VERSION 5.7 ;
BUSBITCHARS "[]" ;
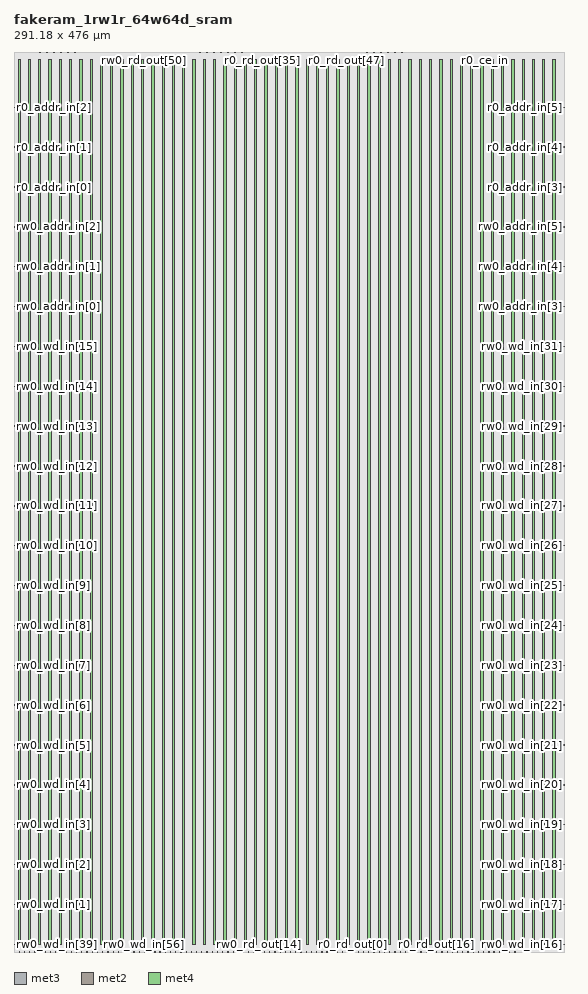
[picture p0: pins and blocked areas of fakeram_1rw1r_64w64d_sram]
MACRO fakeram_1rw1r_64w64d_sram
  FOREIGN fakeram_1rw1r_64w64d_sram 0 0 ;
  SYMMETRY X Y R90 ;
  SIZE 291.180 BY 476.000 ;
  CLASS BLOCK ;
  PIN rw0_wd_in[0]
    DIRECTION INPUT ;
    USE SIGNAL ;
    SHAPE ABUTMENT ;
    PORT
      LAYER met3 ;
      RECT 0.000 3.930 0.900 4.230 ;
    END
  END rw0_wd_in[0]
  PIN rw0_wd_in[1]
    DIRECTION INPUT ;
    USE SIGNAL ;
    SHAPE ABUTMENT ;
    PORT
      LAYER met3 ;
      RECT 0.000 25.010 0.900 25.310 ;
    END
  END rw0_wd_in[1]
  PIN rw0_wd_in[2]
    DIRECTION INPUT ;
    USE SIGNAL ;
    SHAPE ABUTMENT ;
    PORT
      LAYER met3 ;
      RECT 0.000 46.090 0.900 46.390 ;
    END
  END rw0_wd_in[2]
  PIN rw0_wd_in[3]
    DIRECTION INPUT ;
    USE SIGNAL ;
    SHAPE ABUTMENT ;
    PORT
      LAYER met3 ;
      RECT 0.000 67.170 0.900 67.470 ;
    END
  END rw0_wd_in[3]
  PIN rw0_wd_in[4]
    DIRECTION INPUT ;
    USE SIGNAL ;
    SHAPE ABUTMENT ;
    PORT
      LAYER met3 ;
      RECT 0.000 88.250 0.900 88.550 ;
    END
  END rw0_wd_in[4]
  PIN rw0_wd_in[5]
    DIRECTION INPUT ;
    USE SIGNAL ;
    SHAPE ABUTMENT ;
    PORT
      LAYER met3 ;
      RECT 0.000 109.330 0.900 109.630 ;
    END
  END rw0_wd_in[5]
  PIN rw0_wd_in[6]
    DIRECTION INPUT ;
    USE SIGNAL ;
    SHAPE ABUTMENT ;
    PORT
      LAYER met3 ;
      RECT 0.000 130.410 0.900 130.710 ;
    END
  END rw0_wd_in[6]
  PIN rw0_wd_in[7]
    DIRECTION INPUT ;
    USE SIGNAL ;
    SHAPE ABUTMENT ;
    PORT
      LAYER met3 ;
      RECT 0.000 151.490 0.900 151.790 ;
    END
  END rw0_wd_in[7]
  PIN rw0_wd_in[8]
    DIRECTION INPUT ;
    USE SIGNAL ;
    SHAPE ABUTMENT ;
    PORT
      LAYER met3 ;
      RECT 0.000 172.570 0.900 172.870 ;
    END
  END rw0_wd_in[8]
  PIN rw0_wd_in[9]
    DIRECTION INPUT ;
    USE SIGNAL ;
    SHAPE ABUTMENT ;
    PORT
      LAYER met3 ;
      RECT 0.000 193.650 0.900 193.950 ;
    END
  END rw0_wd_in[9]
  PIN rw0_wd_in[10]
    DIRECTION INPUT ;
    USE SIGNAL ;
    SHAPE ABUTMENT ;
    PORT
      LAYER met3 ;
      RECT 0.000 214.730 0.900 215.030 ;
    END
  END rw0_wd_in[10]
  PIN rw0_wd_in[11]
    DIRECTION INPUT ;
    USE SIGNAL ;
    SHAPE ABUTMENT ;
    PORT
      LAYER met3 ;
      RECT 0.000 235.810 0.900 236.110 ;
    END
  END rw0_wd_in[11]
  PIN rw0_wd_in[12]
    DIRECTION INPUT ;
    USE SIGNAL ;
    SHAPE ABUTMENT ;
    PORT
      LAYER met3 ;
      RECT 0.000 256.890 0.900 257.190 ;
    END
  END rw0_wd_in[12]
  PIN rw0_wd_in[13]
    DIRECTION INPUT ;
    USE SIGNAL ;
    SHAPE ABUTMENT ;
    PORT
      LAYER met3 ;
      RECT 0.000 277.970 0.900 278.270 ;
    END
  END rw0_wd_in[13]
  PIN rw0_wd_in[14]
    DIRECTION INPUT ;
    USE SIGNAL ;
    SHAPE ABUTMENT ;
    PORT
      LAYER met3 ;
      RECT 0.000 299.050 0.900 299.350 ;
    END
  END rw0_wd_in[14]
  PIN rw0_wd_in[15]
    DIRECTION INPUT ;
    USE SIGNAL ;
    SHAPE ABUTMENT ;
    PORT
      LAYER met3 ;
      RECT 0.000 320.130 0.900 320.430 ;
    END
  END rw0_wd_in[15]
  PIN rw0_wd_in[16]
    DIRECTION INPUT ;
    USE SIGNAL ;
    SHAPE ABUTMENT ;
    PORT
      LAYER met3 ;
      RECT 290.280 3.930 291.180 4.230 ;
    END
  END rw0_wd_in[16]
  PIN rw0_wd_in[17]
    DIRECTION INPUT ;
    USE SIGNAL ;
    SHAPE ABUTMENT ;
    PORT
      LAYER met3 ;
      RECT 290.280 25.010 291.180 25.310 ;
    END
  END rw0_wd_in[17]
  PIN rw0_wd_in[18]
    DIRECTION INPUT ;
    USE SIGNAL ;
    SHAPE ABUTMENT ;
    PORT
      LAYER met3 ;
      RECT 290.280 46.090 291.180 46.390 ;
    END
  END rw0_wd_in[18]
  PIN rw0_wd_in[19]
    DIRECTION INPUT ;
    USE SIGNAL ;
    SHAPE ABUTMENT ;
    PORT
      LAYER met3 ;
      RECT 290.280 67.170 291.180 67.470 ;
    END
  END rw0_wd_in[19]
  PIN rw0_wd_in[20]
    DIRECTION INPUT ;
    USE SIGNAL ;
    SHAPE ABUTMENT ;
    PORT
      LAYER met3 ;
      RECT 290.280 88.250 291.180 88.550 ;
    END
  END rw0_wd_in[20]
  PIN rw0_wd_in[21]
    DIRECTION INPUT ;
    USE SIGNAL ;
    SHAPE ABUTMENT ;
    PORT
      LAYER met3 ;
      RECT 290.280 109.330 291.180 109.630 ;
    END
  END rw0_wd_in[21]
  PIN rw0_wd_in[22]
    DIRECTION INPUT ;
    USE SIGNAL ;
    SHAPE ABUTMENT ;
    PORT
      LAYER met3 ;
      RECT 290.280 130.410 291.180 130.710 ;
    END
  END rw0_wd_in[22]
  PIN rw0_wd_in[23]
    DIRECTION INPUT ;
    USE SIGNAL ;
    SHAPE ABUTMENT ;
    PORT
      LAYER met3 ;
      RECT 290.280 151.490 291.180 151.790 ;
    END
  END rw0_wd_in[23]
  PIN rw0_wd_in[24]
    DIRECTION INPUT ;
    USE SIGNAL ;
    SHAPE ABUTMENT ;
    PORT
      LAYER met3 ;
      RECT 290.280 172.570 291.180 172.870 ;
    END
  END rw0_wd_in[24]
  PIN rw0_wd_in[25]
    DIRECTION INPUT ;
    USE SIGNAL ;
    SHAPE ABUTMENT ;
    PORT
      LAYER met3 ;
      RECT 290.280 193.650 291.180 193.950 ;
    END
  END rw0_wd_in[25]
  PIN rw0_wd_in[26]
    DIRECTION INPUT ;
    USE SIGNAL ;
    SHAPE ABUTMENT ;
    PORT
      LAYER met3 ;
      RECT 290.280 214.730 291.180 215.030 ;
    END
  END rw0_wd_in[26]
  PIN rw0_wd_in[27]
    DIRECTION INPUT ;
    USE SIGNAL ;
    SHAPE ABUTMENT ;
    PORT
      LAYER met3 ;
      RECT 290.280 235.810 291.180 236.110 ;
    END
  END rw0_wd_in[27]
  PIN rw0_wd_in[28]
    DIRECTION INPUT ;
    USE SIGNAL ;
    SHAPE ABUTMENT ;
    PORT
      LAYER met3 ;
      RECT 290.280 256.890 291.180 257.190 ;
    END
  END rw0_wd_in[28]
  PIN rw0_wd_in[29]
    DIRECTION INPUT ;
    USE SIGNAL ;
    SHAPE ABUTMENT ;
    PORT
      LAYER met3 ;
      RECT 290.280 277.970 291.180 278.270 ;
    END
  END rw0_wd_in[29]
  PIN rw0_wd_in[30]
    DIRECTION INPUT ;
    USE SIGNAL ;
    SHAPE ABUTMENT ;
    PORT
      LAYER met3 ;
      RECT 290.280 299.050 291.180 299.350 ;
    END
  END rw0_wd_in[30]
  PIN rw0_wd_in[31]
    DIRECTION INPUT ;
    USE SIGNAL ;
    SHAPE ABUTMENT ;
    PORT
      LAYER met3 ;
      RECT 290.280 320.130 291.180 320.430 ;
    END
  END rw0_wd_in[31]
  PIN rw0_wd_in[32]
    DIRECTION INPUT ;
    USE SIGNAL ;
    SHAPE ABUTMENT ;
    PORT
      LAYER met2 ;
      RECT 2.690 0.000 2.830 0.420 ;
    END
  END rw0_wd_in[32]
  PIN rw0_wd_in[33]
    DIRECTION INPUT ;
    USE SIGNAL ;
    SHAPE ABUTMENT ;
    PORT
      LAYER met2 ;
      RECT 5.450 0.000 5.590 0.420 ;
    END
  END rw0_wd_in[33]
  PIN rw0_wd_in[34]
    DIRECTION INPUT ;
    USE SIGNAL ;
    SHAPE ABUTMENT ;
    PORT
      LAYER met2 ;
      RECT 8.210 0.000 8.350 0.420 ;
    END
  END rw0_wd_in[34]
  PIN rw0_wd_in[35]
    DIRECTION INPUT ;
    USE SIGNAL ;
    SHAPE ABUTMENT ;
    PORT
      LAYER met2 ;
      RECT 10.970 0.000 11.110 0.420 ;
    END
  END rw0_wd_in[35]
  PIN rw0_wd_in[36]
    DIRECTION INPUT ;
    USE SIGNAL ;
    SHAPE ABUTMENT ;
    PORT
      LAYER met2 ;
      RECT 13.730 0.000 13.870 0.420 ;
    END
  END rw0_wd_in[36]
  PIN rw0_wd_in[37]
    DIRECTION INPUT ;
    USE SIGNAL ;
    SHAPE ABUTMENT ;
    PORT
      LAYER met2 ;
      RECT 16.490 0.000 16.630 0.420 ;
    END
  END rw0_wd_in[37]
  PIN rw0_wd_in[38]
    DIRECTION INPUT ;
    USE SIGNAL ;
    SHAPE ABUTMENT ;
    PORT
      LAYER met2 ;
      RECT 19.250 0.000 19.390 0.420 ;
    END
  END rw0_wd_in[38]
  PIN rw0_wd_in[39]
    DIRECTION INPUT ;
    USE SIGNAL ;
    SHAPE ABUTMENT ;
    PORT
      LAYER met2 ;
      RECT 22.010 0.000 22.150 0.420 ;
    END
  END rw0_wd_in[39]
  PIN rw0_wd_in[40]
    DIRECTION INPUT ;
    USE SIGNAL ;
    SHAPE ABUTMENT ;
    PORT
      LAYER met2 ;
      RECT 24.770 0.000 24.910 0.420 ;
    END
  END rw0_wd_in[40]
  PIN rw0_wd_in[41]
    DIRECTION INPUT ;
    USE SIGNAL ;
    SHAPE ABUTMENT ;
    PORT
      LAYER met2 ;
      RECT 27.530 0.000 27.670 0.420 ;
    END
  END rw0_wd_in[41]
  PIN rw0_wd_in[42]
    DIRECTION INPUT ;
    USE SIGNAL ;
    SHAPE ABUTMENT ;
    PORT
      LAYER met2 ;
      RECT 30.290 0.000 30.430 0.420 ;
    END
  END rw0_wd_in[42]
  PIN rw0_wd_in[43]
    DIRECTION INPUT ;
    USE SIGNAL ;
    SHAPE ABUTMENT ;
    PORT
      LAYER met2 ;
      RECT 33.050 0.000 33.190 0.420 ;
    END
  END rw0_wd_in[43]
  PIN rw0_wd_in[44]
    DIRECTION INPUT ;
    USE SIGNAL ;
    SHAPE ABUTMENT ;
    PORT
      LAYER met2 ;
      RECT 35.810 0.000 35.950 0.420 ;
    END
  END rw0_wd_in[44]
  PIN rw0_wd_in[45]
    DIRECTION INPUT ;
    USE SIGNAL ;
    SHAPE ABUTMENT ;
    PORT
      LAYER met2 ;
      RECT 38.570 0.000 38.710 0.420 ;
    END
  END rw0_wd_in[45]
  PIN rw0_wd_in[46]
    DIRECTION INPUT ;
    USE SIGNAL ;
    SHAPE ABUTMENT ;
    PORT
      LAYER met2 ;
      RECT 41.330 0.000 41.470 0.420 ;
    END
  END rw0_wd_in[46]
  PIN rw0_wd_in[47]
    DIRECTION INPUT ;
    USE SIGNAL ;
    SHAPE ABUTMENT ;
    PORT
      LAYER met2 ;
      RECT 44.090 0.000 44.230 0.420 ;
    END
  END rw0_wd_in[47]
  PIN rw0_wd_in[48]
    DIRECTION INPUT ;
    USE SIGNAL ;
    SHAPE ABUTMENT ;
    PORT
      LAYER met2 ;
      RECT 46.850 0.000 46.990 0.420 ;
    END
  END rw0_wd_in[48]
  PIN rw0_wd_in[49]
    DIRECTION INPUT ;
    USE SIGNAL ;
    SHAPE ABUTMENT ;
    PORT
      LAYER met2 ;
      RECT 49.610 0.000 49.750 0.420 ;
    END
  END rw0_wd_in[49]
  PIN rw0_wd_in[50]
    DIRECTION INPUT ;
    USE SIGNAL ;
    SHAPE ABUTMENT ;
    PORT
      LAYER met2 ;
      RECT 52.370 0.000 52.510 0.420 ;
    END
  END rw0_wd_in[50]
  PIN rw0_wd_in[51]
    DIRECTION INPUT ;
    USE SIGNAL ;
    SHAPE ABUTMENT ;
    PORT
      LAYER met2 ;
      RECT 55.130 0.000 55.270 0.420 ;
    END
  END rw0_wd_in[51]
  PIN rw0_wd_in[52]
    DIRECTION INPUT ;
    USE SIGNAL ;
    SHAPE ABUTMENT ;
    PORT
      LAYER met2 ;
      RECT 57.890 0.000 58.030 0.420 ;
    END
  END rw0_wd_in[52]
  PIN rw0_wd_in[53]
    DIRECTION INPUT ;
    USE SIGNAL ;
    SHAPE ABUTMENT ;
    PORT
      LAYER met2 ;
      RECT 60.650 0.000 60.790 0.420 ;
    END
  END rw0_wd_in[53]
  PIN rw0_wd_in[54]
    DIRECTION INPUT ;
    USE SIGNAL ;
    SHAPE ABUTMENT ;
    PORT
      LAYER met2 ;
      RECT 63.410 0.000 63.550 0.420 ;
    END
  END rw0_wd_in[54]
  PIN rw0_wd_in[55]
    DIRECTION INPUT ;
    USE SIGNAL ;
    SHAPE ABUTMENT ;
    PORT
      LAYER met2 ;
      RECT 66.170 0.000 66.310 0.420 ;
    END
  END rw0_wd_in[55]
  PIN rw0_wd_in[56]
    DIRECTION INPUT ;
    USE SIGNAL ;
    SHAPE ABUTMENT ;
    PORT
      LAYER met2 ;
      RECT 68.930 0.000 69.070 0.420 ;
    END
  END rw0_wd_in[56]
  PIN rw0_wd_in[57]
    DIRECTION INPUT ;
    USE SIGNAL ;
    SHAPE ABUTMENT ;
    PORT
      LAYER met2 ;
      RECT 71.690 0.000 71.830 0.420 ;
    END
  END rw0_wd_in[57]
  PIN rw0_wd_in[58]
    DIRECTION INPUT ;
    USE SIGNAL ;
    SHAPE ABUTMENT ;
    PORT
      LAYER met2 ;
      RECT 74.450 0.000 74.590 0.420 ;
    END
  END rw0_wd_in[58]
  PIN rw0_wd_in[59]
    DIRECTION INPUT ;
    USE SIGNAL ;
    SHAPE ABUTMENT ;
    PORT
      LAYER met2 ;
      RECT 77.210 0.000 77.350 0.420 ;
    END
  END rw0_wd_in[59]
  PIN rw0_wd_in[60]
    DIRECTION INPUT ;
    USE SIGNAL ;
    SHAPE ABUTMENT ;
    PORT
      LAYER met2 ;
      RECT 79.970 0.000 80.110 0.420 ;
    END
  END rw0_wd_in[60]
  PIN rw0_wd_in[61]
    DIRECTION INPUT ;
    USE SIGNAL ;
    SHAPE ABUTMENT ;
    PORT
      LAYER met2 ;
      RECT 82.730 0.000 82.870 0.420 ;
    END
  END rw0_wd_in[61]
  PIN rw0_wd_in[62]
    DIRECTION INPUT ;
    USE SIGNAL ;
    SHAPE ABUTMENT ;
    PORT
      LAYER met2 ;
      RECT 85.490 0.000 85.630 0.420 ;
    END
  END rw0_wd_in[62]
  PIN rw0_wd_in[63]
    DIRECTION INPUT ;
    USE SIGNAL ;
    SHAPE ABUTMENT ;
    PORT
      LAYER met2 ;
      RECT 88.250 0.000 88.390 0.420 ;
    END
  END rw0_wd_in[63]
  PIN rw0_rd_out[0]
    DIRECTION OUTPUT ;
    USE SIGNAL ;
    SHAPE ABUTMENT ;
    PORT
      LAYER met2 ;
      RECT 91.010 0.000 91.150 0.420 ;
    END
  END rw0_rd_out[0]
  PIN rw0_rd_out[1]
    DIRECTION OUTPUT ;
    USE SIGNAL ;
    SHAPE ABUTMENT ;
    PORT
      LAYER met2 ;
      RECT 93.770 0.000 93.910 0.420 ;
    END
  END rw0_rd_out[1]
  PIN rw0_rd_out[2]
    DIRECTION OUTPUT ;
    USE SIGNAL ;
    SHAPE ABUTMENT ;
    PORT
      LAYER met2 ;
      RECT 96.530 0.000 96.670 0.420 ;
    END
  END rw0_rd_out[2]
  PIN rw0_rd_out[3]
    DIRECTION OUTPUT ;
    USE SIGNAL ;
    SHAPE ABUTMENT ;
    PORT
      LAYER met2 ;
      RECT 99.290 0.000 99.430 0.420 ;
    END
  END rw0_rd_out[3]
  PIN rw0_rd_out[4]
    DIRECTION OUTPUT ;
    USE SIGNAL ;
    SHAPE ABUTMENT ;
    PORT
      LAYER met2 ;
      RECT 102.050 0.000 102.190 0.420 ;
    END
  END rw0_rd_out[4]
  PIN rw0_rd_out[5]
    DIRECTION OUTPUT ;
    USE SIGNAL ;
    SHAPE ABUTMENT ;
    PORT
      LAYER met2 ;
      RECT 104.810 0.000 104.950 0.420 ;
    END
  END rw0_rd_out[5]
  PIN rw0_rd_out[6]
    DIRECTION OUTPUT ;
    USE SIGNAL ;
    SHAPE ABUTMENT ;
    PORT
      LAYER met2 ;
      RECT 107.570 0.000 107.710 0.420 ;
    END
  END rw0_rd_out[6]
  PIN rw0_rd_out[7]
    DIRECTION OUTPUT ;
    USE SIGNAL ;
    SHAPE ABUTMENT ;
    PORT
      LAYER met2 ;
      RECT 110.330 0.000 110.470 0.420 ;
    END
  END rw0_rd_out[7]
  PIN rw0_rd_out[8]
    DIRECTION OUTPUT ;
    USE SIGNAL ;
    SHAPE ABUTMENT ;
    PORT
      LAYER met2 ;
      RECT 113.090 0.000 113.230 0.420 ;
    END
  END rw0_rd_out[8]
  PIN rw0_rd_out[9]
    DIRECTION OUTPUT ;
    USE SIGNAL ;
    SHAPE ABUTMENT ;
    PORT
      LAYER met2 ;
      RECT 115.850 0.000 115.990 0.420 ;
    END
  END rw0_rd_out[9]
  PIN rw0_rd_out[10]
    DIRECTION OUTPUT ;
    USE SIGNAL ;
    SHAPE ABUTMENT ;
    PORT
      LAYER met2 ;
      RECT 118.610 0.000 118.750 0.420 ;
    END
  END rw0_rd_out[10]
  PIN rw0_rd_out[11]
    DIRECTION OUTPUT ;
    USE SIGNAL ;
    SHAPE ABUTMENT ;
    PORT
      LAYER met2 ;
      RECT 121.370 0.000 121.510 0.420 ;
    END
  END rw0_rd_out[11]
  PIN rw0_rd_out[12]
    DIRECTION OUTPUT ;
    USE SIGNAL ;
    SHAPE ABUTMENT ;
    PORT
      LAYER met2 ;
      RECT 124.130 0.000 124.270 0.420 ;
    END
  END rw0_rd_out[12]
  PIN rw0_rd_out[13]
    DIRECTION OUTPUT ;
    USE SIGNAL ;
    SHAPE ABUTMENT ;
    PORT
      LAYER met2 ;
      RECT 126.890 0.000 127.030 0.420 ;
    END
  END rw0_rd_out[13]
  PIN rw0_rd_out[14]
    DIRECTION OUTPUT ;
    USE SIGNAL ;
    SHAPE ABUTMENT ;
    PORT
      LAYER met2 ;
      RECT 129.650 0.000 129.790 0.420 ;
    END
  END rw0_rd_out[14]
  PIN rw0_rd_out[15]
    DIRECTION OUTPUT ;
    USE SIGNAL ;
    SHAPE ABUTMENT ;
    PORT
      LAYER met2 ;
      RECT 132.410 0.000 132.550 0.420 ;
    END
  END rw0_rd_out[15]
  PIN rw0_rd_out[16]
    DIRECTION OUTPUT ;
    USE SIGNAL ;
    SHAPE ABUTMENT ;
    PORT
      LAYER met2 ;
      RECT 135.170 0.000 135.310 0.420 ;
    END
  END rw0_rd_out[16]
  PIN rw0_rd_out[17]
    DIRECTION OUTPUT ;
    USE SIGNAL ;
    SHAPE ABUTMENT ;
    PORT
      LAYER met2 ;
      RECT 137.930 0.000 138.070 0.420 ;
    END
  END rw0_rd_out[17]
  PIN rw0_rd_out[18]
    DIRECTION OUTPUT ;
    USE SIGNAL ;
    SHAPE ABUTMENT ;
    PORT
      LAYER met2 ;
      RECT 140.690 0.000 140.830 0.420 ;
    END
  END rw0_rd_out[18]
  PIN rw0_rd_out[19]
    DIRECTION OUTPUT ;
    USE SIGNAL ;
    SHAPE ABUTMENT ;
    PORT
      LAYER met2 ;
      RECT 143.450 0.000 143.590 0.420 ;
    END
  END rw0_rd_out[19]
  PIN rw0_rd_out[20]
    DIRECTION OUTPUT ;
    USE SIGNAL ;
    SHAPE ABUTMENT ;
    PORT
      LAYER met2 ;
      RECT 146.210 0.000 146.350 0.420 ;
    END
  END rw0_rd_out[20]
  PIN rw0_rd_out[21]
    DIRECTION OUTPUT ;
    USE SIGNAL ;
    SHAPE ABUTMENT ;
    PORT
      LAYER met2 ;
      RECT 148.970 0.000 149.110 0.420 ;
    END
  END rw0_rd_out[21]
  PIN rw0_rd_out[22]
    DIRECTION OUTPUT ;
    USE SIGNAL ;
    SHAPE ABUTMENT ;
    PORT
      LAYER met2 ;
      RECT 151.730 0.000 151.870 0.420 ;
    END
  END rw0_rd_out[22]
  PIN rw0_rd_out[23]
    DIRECTION OUTPUT ;
    USE SIGNAL ;
    SHAPE ABUTMENT ;
    PORT
      LAYER met2 ;
      RECT 154.490 0.000 154.630 0.420 ;
    END
  END rw0_rd_out[23]
  PIN rw0_rd_out[24]
    DIRECTION OUTPUT ;
    USE SIGNAL ;
    SHAPE ABUTMENT ;
    PORT
      LAYER met2 ;
      RECT 157.250 0.000 157.390 0.420 ;
    END
  END rw0_rd_out[24]
  PIN rw0_rd_out[25]
    DIRECTION OUTPUT ;
    USE SIGNAL ;
    SHAPE ABUTMENT ;
    PORT
      LAYER met2 ;
      RECT 160.010 0.000 160.150 0.420 ;
    END
  END rw0_rd_out[25]
  PIN rw0_rd_out[26]
    DIRECTION OUTPUT ;
    USE SIGNAL ;
    SHAPE ABUTMENT ;
    PORT
      LAYER met2 ;
      RECT 162.770 0.000 162.910 0.420 ;
    END
  END rw0_rd_out[26]
  PIN rw0_rd_out[27]
    DIRECTION OUTPUT ;
    USE SIGNAL ;
    SHAPE ABUTMENT ;
    PORT
      LAYER met2 ;
      RECT 165.530 0.000 165.670 0.420 ;
    END
  END rw0_rd_out[27]
  PIN rw0_rd_out[28]
    DIRECTION OUTPUT ;
    USE SIGNAL ;
    SHAPE ABUTMENT ;
    PORT
      LAYER met2 ;
      RECT 168.290 0.000 168.430 0.420 ;
    END
  END rw0_rd_out[28]
  PIN rw0_rd_out[29]
    DIRECTION OUTPUT ;
    USE SIGNAL ;
    SHAPE ABUTMENT ;
    PORT
      LAYER met2 ;
      RECT 171.050 0.000 171.190 0.420 ;
    END
  END rw0_rd_out[29]
  PIN rw0_rd_out[30]
    DIRECTION OUTPUT ;
    USE SIGNAL ;
    SHAPE ABUTMENT ;
    PORT
      LAYER met2 ;
      RECT 173.810 0.000 173.950 0.420 ;
    END
  END rw0_rd_out[30]
  PIN rw0_rd_out[31]
    DIRECTION OUTPUT ;
    USE SIGNAL ;
    SHAPE ABUTMENT ;
    PORT
      LAYER met2 ;
      RECT 176.570 0.000 176.710 0.420 ;
    END
  END rw0_rd_out[31]
  PIN rw0_rd_out[32]
    DIRECTION OUTPUT ;
    USE SIGNAL ;
    SHAPE ABUTMENT ;
    PORT
      LAYER met2 ;
      RECT 2.690 475.580 2.830 476.000 ;
    END
  END rw0_rd_out[32]
  PIN rw0_rd_out[33]
    DIRECTION OUTPUT ;
    USE SIGNAL ;
    SHAPE ABUTMENT ;
    PORT
      LAYER met2 ;
      RECT 6.370 475.580 6.510 476.000 ;
    END
  END rw0_rd_out[33]
  PIN rw0_rd_out[34]
    DIRECTION OUTPUT ;
    USE SIGNAL ;
    SHAPE ABUTMENT ;
    PORT
      LAYER met2 ;
      RECT 10.050 475.580 10.190 476.000 ;
    END
  END rw0_rd_out[34]
  PIN rw0_rd_out[35]
    DIRECTION OUTPUT ;
    USE SIGNAL ;
    SHAPE ABUTMENT ;
    PORT
      LAYER met2 ;
      RECT 13.730 475.580 13.870 476.000 ;
    END
  END rw0_rd_out[35]
  PIN rw0_rd_out[36]
    DIRECTION OUTPUT ;
    USE SIGNAL ;
    SHAPE ABUTMENT ;
    PORT
      LAYER met2 ;
      RECT 17.410 475.580 17.550 476.000 ;
    END
  END rw0_rd_out[36]
  PIN rw0_rd_out[37]
    DIRECTION OUTPUT ;
    USE SIGNAL ;
    SHAPE ABUTMENT ;
    PORT
      LAYER met2 ;
      RECT 21.090 475.580 21.230 476.000 ;
    END
  END rw0_rd_out[37]
  PIN rw0_rd_out[38]
    DIRECTION OUTPUT ;
    USE SIGNAL ;
    SHAPE ABUTMENT ;
    PORT
      LAYER met2 ;
      RECT 24.770 475.580 24.910 476.000 ;
    END
  END rw0_rd_out[38]
  PIN rw0_rd_out[39]
    DIRECTION OUTPUT ;
    USE SIGNAL ;
    SHAPE ABUTMENT ;
    PORT
      LAYER met2 ;
      RECT 28.450 475.580 28.590 476.000 ;
    END
  END rw0_rd_out[39]
  PIN rw0_rd_out[40]
    DIRECTION OUTPUT ;
    USE SIGNAL ;
    SHAPE ABUTMENT ;
    PORT
      LAYER met2 ;
      RECT 32.130 475.580 32.270 476.000 ;
    END
  END rw0_rd_out[40]
  PIN rw0_rd_out[41]
    DIRECTION OUTPUT ;
    USE SIGNAL ;
    SHAPE ABUTMENT ;
    PORT
      LAYER met2 ;
      RECT 35.810 475.580 35.950 476.000 ;
    END
  END rw0_rd_out[41]
  PIN rw0_rd_out[42]
    DIRECTION OUTPUT ;
    USE SIGNAL ;
    SHAPE ABUTMENT ;
    PORT
      LAYER met2 ;
      RECT 39.490 475.580 39.630 476.000 ;
    END
  END rw0_rd_out[42]
  PIN rw0_rd_out[43]
    DIRECTION OUTPUT ;
    USE SIGNAL ;
    SHAPE ABUTMENT ;
    PORT
      LAYER met2 ;
      RECT 43.170 475.580 43.310 476.000 ;
    END
  END rw0_rd_out[43]
  PIN rw0_rd_out[44]
    DIRECTION OUTPUT ;
    USE SIGNAL ;
    SHAPE ABUTMENT ;
    PORT
      LAYER met2 ;
      RECT 46.850 475.580 46.990 476.000 ;
    END
  END rw0_rd_out[44]
  PIN rw0_rd_out[45]
    DIRECTION OUTPUT ;
    USE SIGNAL ;
    SHAPE ABUTMENT ;
    PORT
      LAYER met2 ;
      RECT 50.530 475.580 50.670 476.000 ;
    END
  END rw0_rd_out[45]
  PIN rw0_rd_out[46]
    DIRECTION OUTPUT ;
    USE SIGNAL ;
    SHAPE ABUTMENT ;
    PORT
      LAYER met2 ;
      RECT 54.210 475.580 54.350 476.000 ;
    END
  END rw0_rd_out[46]
  PIN rw0_rd_out[47]
    DIRECTION OUTPUT ;
    USE SIGNAL ;
    SHAPE ABUTMENT ;
    PORT
      LAYER met2 ;
      RECT 57.890 475.580 58.030 476.000 ;
    END
  END rw0_rd_out[47]
  PIN rw0_rd_out[48]
    DIRECTION OUTPUT ;
    USE SIGNAL ;
    SHAPE ABUTMENT ;
    PORT
      LAYER met2 ;
      RECT 61.570 475.580 61.710 476.000 ;
    END
  END rw0_rd_out[48]
  PIN rw0_rd_out[49]
    DIRECTION OUTPUT ;
    USE SIGNAL ;
    SHAPE ABUTMENT ;
    PORT
      LAYER met2 ;
      RECT 65.250 475.580 65.390 476.000 ;
    END
  END rw0_rd_out[49]
  PIN rw0_rd_out[50]
    DIRECTION OUTPUT ;
    USE SIGNAL ;
    SHAPE ABUTMENT ;
    PORT
      LAYER met2 ;
      RECT 68.930 475.580 69.070 476.000 ;
    END
  END rw0_rd_out[50]
  PIN rw0_rd_out[51]
    DIRECTION OUTPUT ;
    USE SIGNAL ;
    SHAPE ABUTMENT ;
    PORT
      LAYER met2 ;
      RECT 72.610 475.580 72.750 476.000 ;
    END
  END rw0_rd_out[51]
  PIN rw0_rd_out[52]
    DIRECTION OUTPUT ;
    USE SIGNAL ;
    SHAPE ABUTMENT ;
    PORT
      LAYER met2 ;
      RECT 76.290 475.580 76.430 476.000 ;
    END
  END rw0_rd_out[52]
  PIN rw0_rd_out[53]
    DIRECTION OUTPUT ;
    USE SIGNAL ;
    SHAPE ABUTMENT ;
    PORT
      LAYER met2 ;
      RECT 79.970 475.580 80.110 476.000 ;
    END
  END rw0_rd_out[53]
  PIN rw0_rd_out[54]
    DIRECTION OUTPUT ;
    USE SIGNAL ;
    SHAPE ABUTMENT ;
    PORT
      LAYER met2 ;
      RECT 83.650 475.580 83.790 476.000 ;
    END
  END rw0_rd_out[54]
  PIN rw0_rd_out[55]
    DIRECTION OUTPUT ;
    USE SIGNAL ;
    SHAPE ABUTMENT ;
    PORT
      LAYER met2 ;
      RECT 87.330 475.580 87.470 476.000 ;
    END
  END rw0_rd_out[55]
  PIN rw0_rd_out[56]
    DIRECTION OUTPUT ;
    USE SIGNAL ;
    SHAPE ABUTMENT ;
    PORT
      LAYER met2 ;
      RECT 91.010 475.580 91.150 476.000 ;
    END
  END rw0_rd_out[56]
  PIN rw0_rd_out[57]
    DIRECTION OUTPUT ;
    USE SIGNAL ;
    SHAPE ABUTMENT ;
    PORT
      LAYER met2 ;
      RECT 94.690 475.580 94.830 476.000 ;
    END
  END rw0_rd_out[57]
  PIN rw0_rd_out[58]
    DIRECTION OUTPUT ;
    USE SIGNAL ;
    SHAPE ABUTMENT ;
    PORT
      LAYER met2 ;
      RECT 98.370 475.580 98.510 476.000 ;
    END
  END rw0_rd_out[58]
  PIN rw0_rd_out[59]
    DIRECTION OUTPUT ;
    USE SIGNAL ;
    SHAPE ABUTMENT ;
    PORT
      LAYER met2 ;
      RECT 102.050 475.580 102.190 476.000 ;
    END
  END rw0_rd_out[59]
  PIN rw0_rd_out[60]
    DIRECTION OUTPUT ;
    USE SIGNAL ;
    SHAPE ABUTMENT ;
    PORT
      LAYER met2 ;
      RECT 105.730 475.580 105.870 476.000 ;
    END
  END rw0_rd_out[60]
  PIN rw0_rd_out[61]
    DIRECTION OUTPUT ;
    USE SIGNAL ;
    SHAPE ABUTMENT ;
    PORT
      LAYER met2 ;
      RECT 109.410 475.580 109.550 476.000 ;
    END
  END rw0_rd_out[61]
  PIN rw0_rd_out[62]
    DIRECTION OUTPUT ;
    USE SIGNAL ;
    SHAPE ABUTMENT ;
    PORT
      LAYER met2 ;
      RECT 113.090 475.580 113.230 476.000 ;
    END
  END rw0_rd_out[62]
  PIN rw0_rd_out[63]
    DIRECTION OUTPUT ;
    USE SIGNAL ;
    SHAPE ABUTMENT ;
    PORT
      LAYER met2 ;
      RECT 116.770 475.580 116.910 476.000 ;
    END
  END rw0_rd_out[63]
  PIN r0_rd_out[0]
    DIRECTION OUTPUT ;
    USE SIGNAL ;
    SHAPE ABUTMENT ;
    PORT
      LAYER met2 ;
      RECT 179.330 0.000 179.470 0.420 ;
    END
  END r0_rd_out[0]
  PIN r0_rd_out[1]
    DIRECTION OUTPUT ;
    USE SIGNAL ;
    SHAPE ABUTMENT ;
    PORT
      LAYER met2 ;
      RECT 182.090 0.000 182.230 0.420 ;
    END
  END r0_rd_out[1]
  PIN r0_rd_out[2]
    DIRECTION OUTPUT ;
    USE SIGNAL ;
    SHAPE ABUTMENT ;
    PORT
      LAYER met2 ;
      RECT 184.850 0.000 184.990 0.420 ;
    END
  END r0_rd_out[2]
  PIN r0_rd_out[3]
    DIRECTION OUTPUT ;
    USE SIGNAL ;
    SHAPE ABUTMENT ;
    PORT
      LAYER met2 ;
      RECT 187.610 0.000 187.750 0.420 ;
    END
  END r0_rd_out[3]
  PIN r0_rd_out[4]
    DIRECTION OUTPUT ;
    USE SIGNAL ;
    SHAPE ABUTMENT ;
    PORT
      LAYER met2 ;
      RECT 190.370 0.000 190.510 0.420 ;
    END
  END r0_rd_out[4]
  PIN r0_rd_out[5]
    DIRECTION OUTPUT ;
    USE SIGNAL ;
    SHAPE ABUTMENT ;
    PORT
      LAYER met2 ;
      RECT 193.130 0.000 193.270 0.420 ;
    END
  END r0_rd_out[5]
  PIN r0_rd_out[6]
    DIRECTION OUTPUT ;
    USE SIGNAL ;
    SHAPE ABUTMENT ;
    PORT
      LAYER met2 ;
      RECT 195.890 0.000 196.030 0.420 ;
    END
  END r0_rd_out[6]
  PIN r0_rd_out[7]
    DIRECTION OUTPUT ;
    USE SIGNAL ;
    SHAPE ABUTMENT ;
    PORT
      LAYER met2 ;
      RECT 198.650 0.000 198.790 0.420 ;
    END
  END r0_rd_out[7]
  PIN r0_rd_out[8]
    DIRECTION OUTPUT ;
    USE SIGNAL ;
    SHAPE ABUTMENT ;
    PORT
      LAYER met2 ;
      RECT 201.410 0.000 201.550 0.420 ;
    END
  END r0_rd_out[8]
  PIN r0_rd_out[9]
    DIRECTION OUTPUT ;
    USE SIGNAL ;
    SHAPE ABUTMENT ;
    PORT
      LAYER met2 ;
      RECT 204.170 0.000 204.310 0.420 ;
    END
  END r0_rd_out[9]
  PIN r0_rd_out[10]
    DIRECTION OUTPUT ;
    USE SIGNAL ;
    SHAPE ABUTMENT ;
    PORT
      LAYER met2 ;
      RECT 206.930 0.000 207.070 0.420 ;
    END
  END r0_rd_out[10]
  PIN r0_rd_out[11]
    DIRECTION OUTPUT ;
    USE SIGNAL ;
    SHAPE ABUTMENT ;
    PORT
      LAYER met2 ;
      RECT 209.690 0.000 209.830 0.420 ;
    END
  END r0_rd_out[11]
  PIN r0_rd_out[12]
    DIRECTION OUTPUT ;
    USE SIGNAL ;
    SHAPE ABUTMENT ;
    PORT
      LAYER met2 ;
      RECT 212.450 0.000 212.590 0.420 ;
    END
  END r0_rd_out[12]
  PIN r0_rd_out[13]
    DIRECTION OUTPUT ;
    USE SIGNAL ;
    SHAPE ABUTMENT ;
    PORT
      LAYER met2 ;
      RECT 215.210 0.000 215.350 0.420 ;
    END
  END r0_rd_out[13]
  PIN r0_rd_out[14]
    DIRECTION OUTPUT ;
    USE SIGNAL ;
    SHAPE ABUTMENT ;
    PORT
      LAYER met2 ;
      RECT 217.970 0.000 218.110 0.420 ;
    END
  END r0_rd_out[14]
  PIN r0_rd_out[15]
    DIRECTION OUTPUT ;
    USE SIGNAL ;
    SHAPE ABUTMENT ;
    PORT
      LAYER met2 ;
      RECT 220.730 0.000 220.870 0.420 ;
    END
  END r0_rd_out[15]
  PIN r0_rd_out[16]
    DIRECTION OUTPUT ;
    USE SIGNAL ;
    SHAPE ABUTMENT ;
    PORT
      LAYER met2 ;
      RECT 223.490 0.000 223.630 0.420 ;
    END
  END r0_rd_out[16]
  PIN r0_rd_out[17]
    DIRECTION OUTPUT ;
    USE SIGNAL ;
    SHAPE ABUTMENT ;
    PORT
      LAYER met2 ;
      RECT 226.250 0.000 226.390 0.420 ;
    END
  END r0_rd_out[17]
  PIN r0_rd_out[18]
    DIRECTION OUTPUT ;
    USE SIGNAL ;
    SHAPE ABUTMENT ;
    PORT
      LAYER met2 ;
      RECT 229.010 0.000 229.150 0.420 ;
    END
  END r0_rd_out[18]
  PIN r0_rd_out[19]
    DIRECTION OUTPUT ;
    USE SIGNAL ;
    SHAPE ABUTMENT ;
    PORT
      LAYER met2 ;
      RECT 231.770 0.000 231.910 0.420 ;
    END
  END r0_rd_out[19]
  PIN r0_rd_out[20]
    DIRECTION OUTPUT ;
    USE SIGNAL ;
    SHAPE ABUTMENT ;
    PORT
      LAYER met2 ;
      RECT 234.530 0.000 234.670 0.420 ;
    END
  END r0_rd_out[20]
  PIN r0_rd_out[21]
    DIRECTION OUTPUT ;
    USE SIGNAL ;
    SHAPE ABUTMENT ;
    PORT
      LAYER met2 ;
      RECT 237.290 0.000 237.430 0.420 ;
    END
  END r0_rd_out[21]
  PIN r0_rd_out[22]
    DIRECTION OUTPUT ;
    USE SIGNAL ;
    SHAPE ABUTMENT ;
    PORT
      LAYER met2 ;
      RECT 240.050 0.000 240.190 0.420 ;
    END
  END r0_rd_out[22]
  PIN r0_rd_out[23]
    DIRECTION OUTPUT ;
    USE SIGNAL ;
    SHAPE ABUTMENT ;
    PORT
      LAYER met2 ;
      RECT 242.810 0.000 242.950 0.420 ;
    END
  END r0_rd_out[23]
  PIN r0_rd_out[24]
    DIRECTION OUTPUT ;
    USE SIGNAL ;
    SHAPE ABUTMENT ;
    PORT
      LAYER met2 ;
      RECT 245.570 0.000 245.710 0.420 ;
    END
  END r0_rd_out[24]
  PIN r0_rd_out[25]
    DIRECTION OUTPUT ;
    USE SIGNAL ;
    SHAPE ABUTMENT ;
    PORT
      LAYER met2 ;
      RECT 248.330 0.000 248.470 0.420 ;
    END
  END r0_rd_out[25]
  PIN r0_rd_out[26]
    DIRECTION OUTPUT ;
    USE SIGNAL ;
    SHAPE ABUTMENT ;
    PORT
      LAYER met2 ;
      RECT 251.090 0.000 251.230 0.420 ;
    END
  END r0_rd_out[26]
  PIN r0_rd_out[27]
    DIRECTION OUTPUT ;
    USE SIGNAL ;
    SHAPE ABUTMENT ;
    PORT
      LAYER met2 ;
      RECT 253.850 0.000 253.990 0.420 ;
    END
  END r0_rd_out[27]
  PIN r0_rd_out[28]
    DIRECTION OUTPUT ;
    USE SIGNAL ;
    SHAPE ABUTMENT ;
    PORT
      LAYER met2 ;
      RECT 256.610 0.000 256.750 0.420 ;
    END
  END r0_rd_out[28]
  PIN r0_rd_out[29]
    DIRECTION OUTPUT ;
    USE SIGNAL ;
    SHAPE ABUTMENT ;
    PORT
      LAYER met2 ;
      RECT 259.370 0.000 259.510 0.420 ;
    END
  END r0_rd_out[29]
  PIN r0_rd_out[30]
    DIRECTION OUTPUT ;
    USE SIGNAL ;
    SHAPE ABUTMENT ;
    PORT
      LAYER met2 ;
      RECT 262.130 0.000 262.270 0.420 ;
    END
  END r0_rd_out[30]
  PIN r0_rd_out[31]
    DIRECTION OUTPUT ;
    USE SIGNAL ;
    SHAPE ABUTMENT ;
    PORT
      LAYER met2 ;
      RECT 264.890 0.000 265.030 0.420 ;
    END
  END r0_rd_out[31]
  PIN r0_rd_out[32]
    DIRECTION OUTPUT ;
    USE SIGNAL ;
    SHAPE ABUTMENT ;
    PORT
      LAYER met2 ;
      RECT 120.450 475.580 120.590 476.000 ;
    END
  END r0_rd_out[32]
  PIN r0_rd_out[33]
    DIRECTION OUTPUT ;
    USE SIGNAL ;
    SHAPE ABUTMENT ;
    PORT
      LAYER met2 ;
      RECT 124.130 475.580 124.270 476.000 ;
    END
  END r0_rd_out[33]
  PIN r0_rd_out[34]
    DIRECTION OUTPUT ;
    USE SIGNAL ;
    SHAPE ABUTMENT ;
    PORT
      LAYER met2 ;
      RECT 127.810 475.580 127.950 476.000 ;
    END
  END r0_rd_out[34]
  PIN r0_rd_out[35]
    DIRECTION OUTPUT ;
    USE SIGNAL ;
    SHAPE ABUTMENT ;
    PORT
      LAYER met2 ;
      RECT 131.490 475.580 131.630 476.000 ;
    END
  END r0_rd_out[35]
  PIN r0_rd_out[36]
    DIRECTION OUTPUT ;
    USE SIGNAL ;
    SHAPE ABUTMENT ;
    PORT
      LAYER met2 ;
      RECT 135.170 475.580 135.310 476.000 ;
    END
  END r0_rd_out[36]
  PIN r0_rd_out[37]
    DIRECTION OUTPUT ;
    USE SIGNAL ;
    SHAPE ABUTMENT ;
    PORT
      LAYER met2 ;
      RECT 138.850 475.580 138.990 476.000 ;
    END
  END r0_rd_out[37]
  PIN r0_rd_out[38]
    DIRECTION OUTPUT ;
    USE SIGNAL ;
    SHAPE ABUTMENT ;
    PORT
      LAYER met2 ;
      RECT 142.530 475.580 142.670 476.000 ;
    END
  END r0_rd_out[38]
  PIN r0_rd_out[39]
    DIRECTION OUTPUT ;
    USE SIGNAL ;
    SHAPE ABUTMENT ;
    PORT
      LAYER met2 ;
      RECT 146.210 475.580 146.350 476.000 ;
    END
  END r0_rd_out[39]
  PIN r0_rd_out[40]
    DIRECTION OUTPUT ;
    USE SIGNAL ;
    SHAPE ABUTMENT ;
    PORT
      LAYER met2 ;
      RECT 149.890 475.580 150.030 476.000 ;
    END
  END r0_rd_out[40]
  PIN r0_rd_out[41]
    DIRECTION OUTPUT ;
    USE SIGNAL ;
    SHAPE ABUTMENT ;
    PORT
      LAYER met2 ;
      RECT 153.570 475.580 153.710 476.000 ;
    END
  END r0_rd_out[41]
  PIN r0_rd_out[42]
    DIRECTION OUTPUT ;
    USE SIGNAL ;
    SHAPE ABUTMENT ;
    PORT
      LAYER met2 ;
      RECT 157.250 475.580 157.390 476.000 ;
    END
  END r0_rd_out[42]
  PIN r0_rd_out[43]
    DIRECTION OUTPUT ;
    USE SIGNAL ;
    SHAPE ABUTMENT ;
    PORT
      LAYER met2 ;
      RECT 160.930 475.580 161.070 476.000 ;
    END
  END r0_rd_out[43]
  PIN r0_rd_out[44]
    DIRECTION OUTPUT ;
    USE SIGNAL ;
    SHAPE ABUTMENT ;
    PORT
      LAYER met2 ;
      RECT 164.610 475.580 164.750 476.000 ;
    END
  END r0_rd_out[44]
  PIN r0_rd_out[45]
    DIRECTION OUTPUT ;
    USE SIGNAL ;
    SHAPE ABUTMENT ;
    PORT
      LAYER met2 ;
      RECT 168.290 475.580 168.430 476.000 ;
    END
  END r0_rd_out[45]
  PIN r0_rd_out[46]
    DIRECTION OUTPUT ;
    USE SIGNAL ;
    SHAPE ABUTMENT ;
    PORT
      LAYER met2 ;
      RECT 171.970 475.580 172.110 476.000 ;
    END
  END r0_rd_out[46]
  PIN r0_rd_out[47]
    DIRECTION OUTPUT ;
    USE SIGNAL ;
    SHAPE ABUTMENT ;
    PORT
      LAYER met2 ;
      RECT 175.650 475.580 175.790 476.000 ;
    END
  END r0_rd_out[47]
  PIN r0_rd_out[48]
    DIRECTION OUTPUT ;
    USE SIGNAL ;
    SHAPE ABUTMENT ;
    PORT
      LAYER met2 ;
      RECT 179.330 475.580 179.470 476.000 ;
    END
  END r0_rd_out[48]
  PIN r0_rd_out[49]
    DIRECTION OUTPUT ;
    USE SIGNAL ;
    SHAPE ABUTMENT ;
    PORT
      LAYER met2 ;
      RECT 183.010 475.580 183.150 476.000 ;
    END
  END r0_rd_out[49]
  PIN r0_rd_out[50]
    DIRECTION OUTPUT ;
    USE SIGNAL ;
    SHAPE ABUTMENT ;
    PORT
      LAYER met2 ;
      RECT 186.690 475.580 186.830 476.000 ;
    END
  END r0_rd_out[50]
  PIN r0_rd_out[51]
    DIRECTION OUTPUT ;
    USE SIGNAL ;
    SHAPE ABUTMENT ;
    PORT
      LAYER met2 ;
      RECT 190.370 475.580 190.510 476.000 ;
    END
  END r0_rd_out[51]
  PIN r0_rd_out[52]
    DIRECTION OUTPUT ;
    USE SIGNAL ;
    SHAPE ABUTMENT ;
    PORT
      LAYER met2 ;
      RECT 194.050 475.580 194.190 476.000 ;
    END
  END r0_rd_out[52]
  PIN r0_rd_out[53]
    DIRECTION OUTPUT ;
    USE SIGNAL ;
    SHAPE ABUTMENT ;
    PORT
      LAYER met2 ;
      RECT 197.730 475.580 197.870 476.000 ;
    END
  END r0_rd_out[53]
  PIN r0_rd_out[54]
    DIRECTION OUTPUT ;
    USE SIGNAL ;
    SHAPE ABUTMENT ;
    PORT
      LAYER met2 ;
      RECT 201.410 475.580 201.550 476.000 ;
    END
  END r0_rd_out[54]
  PIN r0_rd_out[55]
    DIRECTION OUTPUT ;
    USE SIGNAL ;
    SHAPE ABUTMENT ;
    PORT
      LAYER met2 ;
      RECT 205.090 475.580 205.230 476.000 ;
    END
  END r0_rd_out[55]
  PIN r0_rd_out[56]
    DIRECTION OUTPUT ;
    USE SIGNAL ;
    SHAPE ABUTMENT ;
    PORT
      LAYER met2 ;
      RECT 208.770 475.580 208.910 476.000 ;
    END
  END r0_rd_out[56]
  PIN r0_rd_out[57]
    DIRECTION OUTPUT ;
    USE SIGNAL ;
    SHAPE ABUTMENT ;
    PORT
      LAYER met2 ;
      RECT 212.450 475.580 212.590 476.000 ;
    END
  END r0_rd_out[57]
  PIN r0_rd_out[58]
    DIRECTION OUTPUT ;
    USE SIGNAL ;
    SHAPE ABUTMENT ;
    PORT
      LAYER met2 ;
      RECT 216.130 475.580 216.270 476.000 ;
    END
  END r0_rd_out[58]
  PIN r0_rd_out[59]
    DIRECTION OUTPUT ;
    USE SIGNAL ;
    SHAPE ABUTMENT ;
    PORT
      LAYER met2 ;
      RECT 219.810 475.580 219.950 476.000 ;
    END
  END r0_rd_out[59]
  PIN r0_rd_out[60]
    DIRECTION OUTPUT ;
    USE SIGNAL ;
    SHAPE ABUTMENT ;
    PORT
      LAYER met2 ;
      RECT 223.490 475.580 223.630 476.000 ;
    END
  END r0_rd_out[60]
  PIN r0_rd_out[61]
    DIRECTION OUTPUT ;
    USE SIGNAL ;
    SHAPE ABUTMENT ;
    PORT
      LAYER met2 ;
      RECT 227.170 475.580 227.310 476.000 ;
    END
  END r0_rd_out[61]
  PIN r0_rd_out[62]
    DIRECTION OUTPUT ;
    USE SIGNAL ;
    SHAPE ABUTMENT ;
    PORT
      LAYER met2 ;
      RECT 230.850 475.580 230.990 476.000 ;
    END
  END r0_rd_out[62]
  PIN r0_rd_out[63]
    DIRECTION OUTPUT ;
    USE SIGNAL ;
    SHAPE ABUTMENT ;
    PORT
      LAYER met2 ;
      RECT 234.530 475.580 234.670 476.000 ;
    END
  END r0_rd_out[63]
  PIN rw0_addr_in[0]
    DIRECTION INPUT ;
    USE SIGNAL ;
    SHAPE ABUTMENT ;
    PORT
      LAYER met3 ;
      RECT 0.000 341.210 0.900 341.510 ;
    END
  END rw0_addr_in[0]
  PIN rw0_addr_in[1]
    DIRECTION INPUT ;
    USE SIGNAL ;
    SHAPE ABUTMENT ;
    PORT
      LAYER met3 ;
      RECT 0.000 362.290 0.900 362.590 ;
    END
  END rw0_addr_in[1]
  PIN rw0_addr_in[2]
    DIRECTION INPUT ;
    USE SIGNAL ;
    SHAPE ABUTMENT ;
    PORT
      LAYER met3 ;
      RECT 0.000 383.370 0.900 383.670 ;
    END
  END rw0_addr_in[2]
  PIN rw0_addr_in[3]
    DIRECTION INPUT ;
    USE SIGNAL ;
    SHAPE ABUTMENT ;
    PORT
      LAYER met3 ;
      RECT 290.280 341.210 291.180 341.510 ;
    END
  END rw0_addr_in[3]
  PIN rw0_addr_in[4]
    DIRECTION INPUT ;
    USE SIGNAL ;
    SHAPE ABUTMENT ;
    PORT
      LAYER met3 ;
      RECT 290.280 362.290 291.180 362.590 ;
    END
  END rw0_addr_in[4]
  PIN rw0_addr_in[5]
    DIRECTION INPUT ;
    USE SIGNAL ;
    SHAPE ABUTMENT ;
    PORT
      LAYER met3 ;
      RECT 290.280 383.370 291.180 383.670 ;
    END
  END rw0_addr_in[5]
  PIN r0_addr_in[0]
    DIRECTION INPUT ;
    USE SIGNAL ;
    SHAPE ABUTMENT ;
    PORT
      LAYER met3 ;
      RECT 0.000 404.450 0.900 404.750 ;
    END
  END r0_addr_in[0]
  PIN r0_addr_in[1]
    DIRECTION INPUT ;
    USE SIGNAL ;
    SHAPE ABUTMENT ;
    PORT
      LAYER met3 ;
      RECT 0.000 425.530 0.900 425.830 ;
    END
  END r0_addr_in[1]
  PIN r0_addr_in[2]
    DIRECTION INPUT ;
    USE SIGNAL ;
    SHAPE ABUTMENT ;
    PORT
      LAYER met3 ;
      RECT 0.000 446.610 0.900 446.910 ;
    END
  END r0_addr_in[2]
  PIN r0_addr_in[3]
    DIRECTION INPUT ;
    USE SIGNAL ;
    SHAPE ABUTMENT ;
    PORT
      LAYER met3 ;
      RECT 290.280 404.450 291.180 404.750 ;
    END
  END r0_addr_in[3]
  PIN r0_addr_in[4]
    DIRECTION INPUT ;
    USE SIGNAL ;
    SHAPE ABUTMENT ;
    PORT
      LAYER met3 ;
      RECT 290.280 425.530 291.180 425.830 ;
    END
  END r0_addr_in[4]
  PIN r0_addr_in[5]
    DIRECTION INPUT ;
    USE SIGNAL ;
    SHAPE ABUTMENT ;
    PORT
      LAYER met3 ;
      RECT 290.280 446.610 291.180 446.910 ;
    END
  END r0_addr_in[5]
  PIN rw0_we_in
    DIRECTION INPUT ;
    USE SIGNAL ;
    SHAPE ABUTMENT ;
    PORT
      LAYER met2 ;
      RECT 238.210 475.580 238.350 476.000 ;
    END
  END rw0_we_in
  PIN rw0_ce_in
    DIRECTION INPUT ;
    USE SIGNAL ;
    SHAPE ABUTMENT ;
    PORT
      LAYER met2 ;
      RECT 241.890 475.580 242.030 476.000 ;
    END
  END rw0_ce_in
  PIN rw0_clk
    DIRECTION INPUT ;
    USE SIGNAL ;
    SHAPE ABUTMENT ;
    PORT
      LAYER met2 ;
      RECT 245.570 475.580 245.710 476.000 ;
    END
  END rw0_clk
  PIN r0_ce_in
    DIRECTION INPUT ;
    USE SIGNAL ;
    SHAPE ABUTMENT ;
    PORT
      LAYER met2 ;
      RECT 249.250 475.580 249.390 476.000 ;
    END
  END r0_ce_in
  PIN r0_clk
    DIRECTION INPUT ;
    USE SIGNAL ;
    SHAPE ABUTMENT ;
    PORT
      LAYER met2 ;
      RECT 252.930 475.580 253.070 476.000 ;
    END
  END r0_clk
  PIN VSS
    DIRECTION INOUT ;
    USE GROUND ;
    PORT
      LAYER met4 ;
      RECT 2.160 4.080 3.360 471.920 ;
      RECT 13.040 4.080 14.240 471.920 ;
      RECT 23.920 4.080 25.120 471.920 ;
      RECT 34.800 4.080 36.000 471.920 ;
      RECT 45.680 4.080 46.880 471.920 ;
      RECT 56.560 4.080 57.760 471.920 ;
      RECT 67.440 4.080 68.640 471.920 ;
      RECT 78.320 4.080 79.520 471.920 ;
      RECT 89.200 4.080 90.400 471.920 ;
      RECT 100.080 4.080 101.280 471.920 ;
      RECT 110.960 4.080 112.160 471.920 ;
      RECT 121.840 4.080 123.040 471.920 ;
      RECT 132.720 4.080 133.920 471.920 ;
      RECT 143.600 4.080 144.800 471.920 ;
      RECT 154.480 4.080 155.680 471.920 ;
      RECT 165.360 4.080 166.560 471.920 ;
      RECT 176.240 4.080 177.440 471.920 ;
      RECT 187.120 4.080 188.320 471.920 ;
      RECT 198.000 4.080 199.200 471.920 ;
      RECT 208.880 4.080 210.080 471.920 ;
      RECT 219.760 4.080 220.960 471.920 ;
      RECT 230.640 4.080 231.840 471.920 ;
      RECT 241.520 4.080 242.720 471.920 ;
      RECT 252.400 4.080 253.600 471.920 ;
      RECT 263.280 4.080 264.480 471.920 ;
      RECT 274.160 4.080 275.360 471.920 ;
      RECT 285.040 4.080 286.240 471.920 ;
    END
  END VSS
  PIN VDD
    DIRECTION INOUT ;
    USE POWER ;
    PORT
      LAYER met4 ;
      RECT 7.600 4.080 8.800 471.920 ;
      RECT 18.480 4.080 19.680 471.920 ;
      RECT 29.360 4.080 30.560 471.920 ;
      RECT 40.240 4.080 41.440 471.920 ;
      RECT 51.120 4.080 52.320 471.920 ;
      RECT 62.000 4.080 63.200 471.920 ;
      RECT 72.880 4.080 74.080 471.920 ;
      RECT 83.760 4.080 84.960 471.920 ;
      RECT 94.640 4.080 95.840 471.920 ;
      RECT 105.520 4.080 106.720 471.920 ;
      RECT 116.400 4.080 117.600 471.920 ;
      RECT 127.280 4.080 128.480 471.920 ;
      RECT 138.160 4.080 139.360 471.920 ;
      RECT 149.040 4.080 150.240 471.920 ;
      RECT 159.920 4.080 161.120 471.920 ;
      RECT 170.800 4.080 172.000 471.920 ;
      RECT 181.680 4.080 182.880 471.920 ;
      RECT 192.560 4.080 193.760 471.920 ;
      RECT 203.440 4.080 204.640 471.920 ;
      RECT 214.320 4.080 215.520 471.920 ;
      RECT 225.200 4.080 226.400 471.920 ;
      RECT 236.080 4.080 237.280 471.920 ;
      RECT 246.960 4.080 248.160 471.920 ;
      RECT 257.840 4.080 259.040 471.920 ;
      RECT 268.720 4.080 269.920 471.920 ;
      RECT 279.600 4.080 280.800 471.920 ;
    END
  END VDD
  OBS
    LAYER met1 ;
    RECT 0 0 291.180 476.000 ;
    LAYER met2 ;
    RECT 0 0 291.180 476.000 ;
    LAYER met3 ;
    RECT 0 0 291.180 476.000 ;
    LAYER met4 ;
    RECT 0 0 291.180 476.000 ;
  END
END fakeram_1rw1r_64w64d_sram

END LIBRARY
